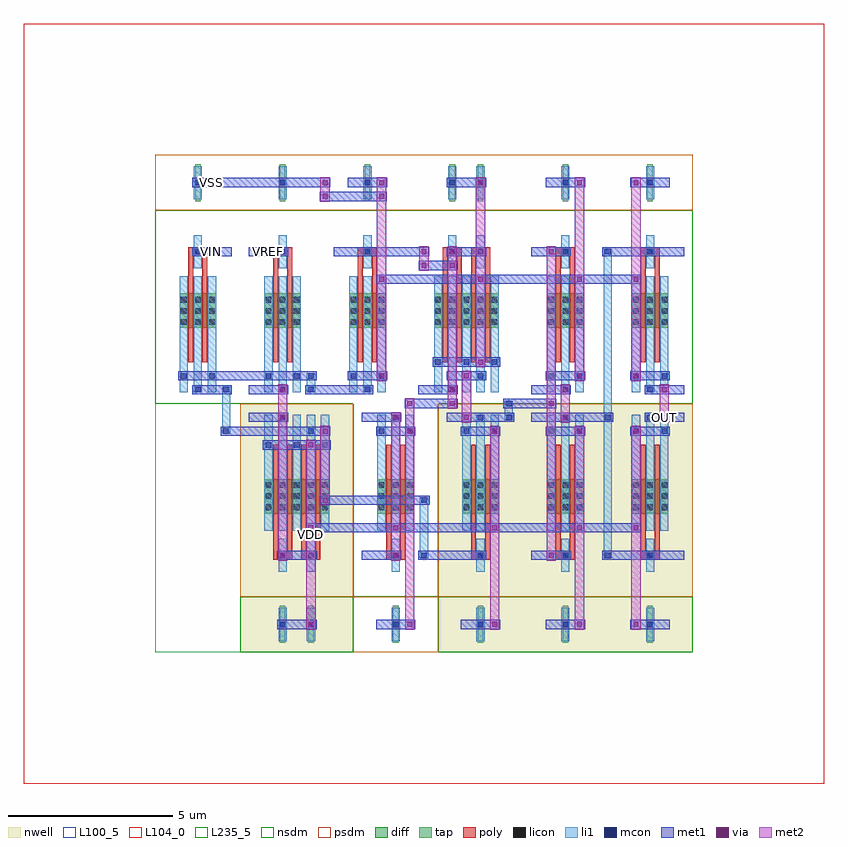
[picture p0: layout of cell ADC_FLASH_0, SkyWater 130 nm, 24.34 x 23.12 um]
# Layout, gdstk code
from math import pi, radians
import gdstk
lib = gdstk.Library(unit=1e-6, precision=1e-09)
def R(c, l, rs):  # rectangles x0, y0, x1, y1
    for r in rs: c.add(gdstk.rectangle(r[:2], r[2:], *l))
def A(c, l, x, y, w, h, nx, ny, dx, dy):  # array of equal rectangles
    R(c, l, [(x+i*dx, y+j*dy, x+i*dx+w, y+j*dy+h) for i in range(nx) for j in range(ny)])
def P(c, l, *ps):  # polygons
    for p in ps: c.add(gdstk.Polygon(p, *l))
nwell = (64, 20)
diff = (65, 20)
tap = (65, 44)
poly = (66, 20)
licon = (66, 44)
li1 = (67, 20)
mcon = (67, 44)
met1 = (68, 20)
via = (68, 44)
met2 = (69, 20)
nsdm = (93, 44)
psdm = (94, 20)
L100_5 = (100, 5)
L104_0 = (104, 0)
L235_5 = (235, 5)

nmos_s_65043269_x1_y1_16 = lib.new_cell('NMOS_S_65043269_X1_Y1_1679391342_1679391343')
R(nmos_s_65043269_x1_y1_16, diff, [(0.735,2.31,1.845,3.36)])
R(nmos_s_65043269_x1_y1_16, tap, [(1.205,6.16,1.375,7.28)])
R(nmos_s_65043269_x1_y1_16, poly, [(1,1.26,1.15,4.62), (1.43,1.26,1.58,4.62), (1,4.485,1.58,4.755)])
A(nmos_s_65043269_x1_y1_16, licon, 0.775, 2.39, 0.17, 0.17, 3, 3, 0.43, 0.34)
R(nmos_s_65043269_x1_y1_16, licon, [(1.205,4.535,1.375,4.705), (1.205,6.635,1.375,6.805)])
A(nmos_s_65043269_x1_y1_16, li1, 0.735, 0.335, 0.25, 3.53, 3, 1, 0.43, 0)
R(nmos_s_65043269_x1_y1_16, li1, [(1.165,4.115,1.415,5.125), (1.165,6.215,1.415,7.225)])
R(nmos_s_65043269_x1_y1_16, mcon, [(1.205,0.335,1.375,0.505), (0.775,0.755,0.945,0.925), (1.635,0.755,1.805,0.925), (1.205,4.535,1.375,4.705), (1.205,6.635,1.375,6.805)])
R(nmos_s_65043269_x1_y1_16, met1, [(0.26,0.28,1.46,0.56), (0.69,0.7,1.89,0.98), (0.26,4.48,1.46,4.76), (0.69,6.58,1.89,6.86)])
R(nmos_s_65043269_x1_y1_16, via, [(1.645,0.765,1.795,0.915), (1.645,6.645,1.795,6.795)])
R(nmos_s_65043269_x1_y1_16, met2, [(1.58,0.68,1.86,6.88)])
R(nmos_s_65043269_x1_y1_16, nsdm, [(0,0,2.58,5.88)])
R(nmos_s_65043269_x1_y1_16, psdm, [(0,5.88,2.58,7.56)])
R(nmos_s_65043269_x1_y1_16, L100_5, [(0,0,2.58,7.56)])

pmos_s_3683112_x1_y1_167 = lib.new_cell('PMOS_S_3683112_X1_Y1_1679391343_1679391343')
R(pmos_s_3683112_x1_y1_167, nwell, [(0,0,2.58,7.56)])
R(pmos_s_3683112_x1_y1_167, diff, [(0.735,2.31,1.845,3.36)])
R(pmos_s_3683112_x1_y1_167, tap, [(1.205,6.16,1.375,7.28)])
R(pmos_s_3683112_x1_y1_167, poly, [(1,1.26,1.15,4.62), (1.43,1.26,1.58,4.62), (1,4.485,1.58,4.755)])
A(pmos_s_3683112_x1_y1_167, licon, 0.775, 2.39, 0.17, 0.17, 3, 3, 0.43, 0.34)
R(pmos_s_3683112_x1_y1_167, licon, [(1.205,4.535,1.375,4.705), (1.205,6.635,1.375,6.805)])
A(pmos_s_3683112_x1_y1_167, li1, 0.735, 0.335, 0.25, 3.53, 3, 1, 0.43, 0)
R(pmos_s_3683112_x1_y1_167, li1, [(1.165,4.115,1.415,5.125), (1.165,6.215,1.415,7.225)])
R(pmos_s_3683112_x1_y1_167, mcon, [(1.205,0.335,1.375,0.505), (0.775,0.755,0.945,0.925), (1.635,0.755,1.805,0.925), (1.205,4.535,1.375,4.705), (1.205,6.635,1.375,6.805)])
R(pmos_s_3683112_x1_y1_167, met1, [(0.26,0.28,1.46,0.56), (0.69,0.7,1.89,0.98), (0.26,4.48,1.46,4.76), (0.69,6.58,1.89,6.86)])
R(pmos_s_3683112_x1_y1_167, via, [(1.645,0.765,1.795,0.915), (1.645,6.645,1.795,6.795)])
R(pmos_s_3683112_x1_y1_167, met2, [(1.58,0.68,1.86,6.88)])
R(pmos_s_3683112_x1_y1_167, nsdm, [(0,5.88,2.58,7.56)])
R(pmos_s_3683112_x1_y1_167, psdm, [(0,0,2.58,5.88)])
R(pmos_s_3683112_x1_y1_167, L100_5, [(0,0,2.58,7.56)])

stage2_inv_60376295_0_0_ = lib.new_cell('STAGE2_INV_60376295_0_0_1679391343')
R(stage2_inv_60376295_0_0_, li1, [(2.455,2.855,2.705,3.025), (2.455,2.855,2.705,3.025), (2.455,2.94,2.705,7.98), (2.455,7.895,2.705,8.065), (2.455,7.895,2.705,8.065), (2.455,7.895,2.705,8.065), (2.455,7.895,2.705,8.065), (2.455,7.895,2.705,8.065), (2.455,7.895,2.705,8.065), (2.455,7.98,2.705,12.18), (2.455,12.095,2.705,12.265), (2.455,12.095,2.705,12.265), (2.455,12.095,2.705,12.265), (2.455,12.095,2.705,12.265), (2.455,12.095,2.705,12.265), (2.455,12.095,2.705,12.265)])
R(stage2_inv_60376295_0_0_, mcon, [(2.495,2.855,2.665,3.025), (2.495,2.855,2.665,3.025), (2.495,7.895,2.665,8.065), (2.495,7.895,2.665,8.065), (2.495,7.895,2.665,8.065), (2.495,7.895,2.665,8.065), (2.495,7.895,2.665,8.065), (2.495,7.895,2.665,8.065), (2.495,12.095,2.665,12.265), (2.495,12.095,2.665,12.265), (2.495,12.095,2.665,12.265), (2.495,12.095,2.665,12.265), (2.495,12.095,2.665,12.265), (2.495,12.095,2.665,12.265)])
R(stage2_inv_60376295_0_0_, met1, [(1.29,2.8,2.58,3.08), (2.41,2.8,2.75,3.08), (2.41,2.8,2.75,3.08), (4.14,2.8,4.46,3.08), (4.14,2.8,4.46,3.08), (1.56,3.64,1.88,3.92), (1.56,3.64,1.88,3.92), (1.72,3.64,3.44,3.92), (3.28,3.64,3.6,3.92), (3.28,3.64,3.6,3.92), (0.7,7,1.02,7.28), (0.7,7,1.02,7.28), (3.71,7,4.03,7.28), (3.71,7,4.03,7.28), (3.71,7,4.03,7.28), (3.71,7,4.03,7.28), (0.7,7.84,1.02,8.12), (0.7,7.84,1.02,8.12), (2.41,7.84,2.75,8.12), (2.41,7.84,2.75,8.12), (2.41,7.84,2.75,8.12), (2.41,7.84,2.75,8.12), (2.41,7.84,2.75,8.12), (2.41,7.84,2.75,8.12), (2.58,7.84,3.87,8.12), (3.71,7.84,4.03,8.12), (3.71,7.84,4.03,8.12), (3.71,7.84,4.03,8.12), (3.71,7.84,4.03,8.12), (1.56,11.2,1.88,11.48), (1.56,11.2,1.88,11.48), (1.72,11.2,3.44,11.48), (3.28,11.2,3.6,11.48), (3.28,11.2,3.6,11.48), (1.29,12.04,2.58,12.32), (2.41,12.04,2.75,12.32), (2.41,12.04,2.75,12.32), (2.41,12.04,2.75,12.32), (2.41,12.04,2.75,12.32), (2.41,12.04,2.75,12.32), (2.41,12.04,2.75,12.32), (4.14,12.04,4.46,12.32), (4.14,12.04,4.46,12.32)])
P(stage2_inv_60376295_0_0_, met1, [(0,0),(0,0),(0,0),(0,0)],
  [(0,0),(0,0),(0,0),(0,0)],
  [(0,0),(0,0),(0,0),(0,0)],
  [(0,0),(0,0),(0,0),(0,0)],
  [(0,0),(0,0),(0,0),(0,0)],
  [(0,0),(0,0),(0,0),(0,0)],
  [(0,0),(0,0),(0,0),(0,0)],
  [(0,0),(0,0),(0,0),(0,0)])
R(stage2_inv_60376295_0_0_, via, [(4.225,2.865,4.375,3.015), (4.225,2.865,4.375,3.015), (1.645,3.705,1.795,3.855), (1.645,3.705,1.795,3.855), (3.365,3.705,3.515,3.855), (3.365,3.705,3.515,3.855), (0.785,7.065,0.935,7.215), (0.785,7.065,0.935,7.215), (3.795,7.065,3.945,7.215), (3.795,7.065,3.945,7.215), (3.795,7.065,3.945,7.215), (3.795,7.065,3.945,7.215), (0.785,7.905,0.935,8.055), (0.785,7.905,0.935,8.055), (3.795,7.905,3.945,8.055), (3.795,7.905,3.945,8.055), (3.795,7.905,3.945,8.055), (3.795,7.905,3.945,8.055), (1.645,11.265,1.795,11.415), (1.645,11.265,1.795,11.415), (3.365,11.265,3.515,11.415), (3.365,11.265,3.515,11.415), (4.225,12.105,4.375,12.255), (4.225,12.105,4.375,12.255)])
R(stage2_inv_60376295_0_0_, met2, [(4.16,2.78,4.44,3.1), (4.16,2.78,4.44,3.1), (4.16,2.94,4.44,12.18), (1.58,3.62,1.86,3.94), (1.58,3.62,1.86,3.94), (3.3,3.62,3.58,3.94), (3.3,3.62,3.58,3.94), (0.72,6.98,1,7.3), (0.72,6.98,1,7.3), (3.73,6.98,4.01,7.3), (3.73,6.98,4.01,7.3), (3.73,6.98,4.01,7.3), (3.73,6.98,4.01,7.3), (0.72,7.14,1,7.98), (3.73,7.14,4.01,7.98), (0.72,7.82,1,8.14), (0.72,7.82,1,8.14), (3.73,7.82,4.01,8.14), (3.73,7.82,4.01,8.14), (3.73,7.82,4.01,8.14), (3.73,7.82,4.01,8.14), (1.58,11.18,1.86,11.5), (1.58,11.18,1.86,11.5), (3.3,11.18,3.58,11.5), (3.3,11.18,3.58,11.5), (4.16,12.02,4.44,12.34), (4.16,12.02,4.44,12.34)])
P(stage2_inv_60376295_0_0_, met2, [(0,0),(0,0),(0,0),(0,0)],
  [(0,0),(0,0),(0,0),(0,0)],
  [(0,0),(0,0),(0,0),(0,0)],
  [(0,0),(0,0),(0,0),(0,0)])
R(stage2_inv_60376295_0_0_, L235_5, [(0,0,5.16,15.12)])
stage2_inv_60376295_0_0_.add(gdstk.Reference(nmos_s_65043269_x1_y1_16, (5.16,7.56), rotation=pi))
stage2_inv_60376295_0_0_.add(gdstk.Reference(nmos_s_65043269_x1_y1_16, (0,7.56), x_reflection=True))
stage2_inv_60376295_0_0_.add(gdstk.Reference(pmos_s_3683112_x1_y1_167, (5.16,7.56), rotation=pi, x_reflection=True))
stage2_inv_60376295_0_0_.add(gdstk.Reference(pmos_s_3683112_x1_y1_167, (0,7.56)))

scm_nmos_72908643_x1_y1_ = lib.new_cell('SCM_NMOS_72908643_X1_Y1_1679391343_1679391342')
R(scm_nmos_72908643_x1_y1_, diff, [(0.735,2.31,2.705,3.36)])
R(scm_nmos_72908643_x1_y1_, tap, [(1.205,6.16,1.375,7.28), (2.065,6.16,2.235,7.28)])
A(scm_nmos_72908643_x1_y1_, poly, 1, 1.26, 0.15, 3.36, 4, 1, 0.43, 0)
R(scm_nmos_72908643_x1_y1_, poly, [(1,4.485,1.58,4.755), (1.86,4.485,2.44,4.755)])
A(scm_nmos_72908643_x1_y1_, licon, 0.775, 2.39, 0.17, 0.17, 3, 3, 0.43, 0.34)
A(scm_nmos_72908643_x1_y1_, licon, 1.635, 2.39, 0.17, 0.17, 3, 3, 0.43, 0.34)
R(scm_nmos_72908643_x1_y1_, licon, [(1.205,4.535,1.375,4.705), (2.065,4.535,2.235,4.705), (1.205,6.635,1.375,6.805), (2.065,6.635,2.235,6.805)])
A(scm_nmos_72908643_x1_y1_, li1, 0.735, 0.335, 0.25, 3.53, 5, 1, 0.43, 0)
R(scm_nmos_72908643_x1_y1_, li1, [(1.165,4.115,1.415,5.125), (2.025,4.115,2.275,5.125), (1.165,6.215,1.415,7.225), (2.025,6.215,2.275,7.225)])
A(scm_nmos_72908643_x1_y1_, mcon, 0.775, 1.175, 0.17, 0.17, 3, 1, 0.86, 0)
R(scm_nmos_72908643_x1_y1_, mcon, [(1.205,0.335,1.375,0.505), (2.065,0.755,2.235,0.925), (1.205,4.535,1.375,4.705), (2.065,4.535,2.235,4.705), (1.205,6.635,1.375,6.805), (2.065,6.635,2.235,6.805)])
R(scm_nmos_72908643_x1_y1_, met1, [(0.26,0.28,1.46,0.56), (1.12,0.7,2.32,0.98), (0.69,1.12,2.75,1.4), (1.12,4.48,2.32,4.76), (1.12,6.58,2.32,6.86)])
R(scm_nmos_72908643_x1_y1_, via, [(1.215,0.345,1.365,0.495), (2.075,1.185,2.225,1.335), (1.215,4.545,1.365,4.695), (2.075,6.645,2.225,6.795)])
R(scm_nmos_72908643_x1_y1_, met2, [(1.15,0.26,1.43,4.78), (2.01,1.1,2.29,6.88)])
R(scm_nmos_72908643_x1_y1_, nsdm, [(0,0,3.44,5.88)])
R(scm_nmos_72908643_x1_y1_, psdm, [(0,5.88,3.44,7.56)])
R(scm_nmos_72908643_x1_y1_, L100_5, [(0,0,3.44,7.56)])

c_nmos_s_65043269_x1_y1_16 = lib.new_cell('NMOS_S_65043269_X1_Y1_1679391342_1679391342')
R(c_nmos_s_65043269_x1_y1_16, diff, [(0.735,2.31,1.845,3.36)])
R(c_nmos_s_65043269_x1_y1_16, tap, [(1.205,6.16,1.375,7.28)])
R(c_nmos_s_65043269_x1_y1_16, poly, [(1,1.26,1.15,4.62), (1.43,1.26,1.58,4.62), (1,4.485,1.58,4.755)])
A(c_nmos_s_65043269_x1_y1_16, licon, 0.775, 2.39, 0.17, 0.17, 3, 3, 0.43, 0.34)
R(c_nmos_s_65043269_x1_y1_16, licon, [(1.205,4.535,1.375,4.705), (1.205,6.635,1.375,6.805)])
A(c_nmos_s_65043269_x1_y1_16, li1, 0.735, 0.335, 0.25, 3.53, 3, 1, 0.43, 0)
R(c_nmos_s_65043269_x1_y1_16, li1, [(1.165,4.115,1.415,5.125), (1.165,6.215,1.415,7.225)])
R(c_nmos_s_65043269_x1_y1_16, mcon, [(1.205,0.335,1.375,0.505), (0.775,0.755,0.945,0.925), (1.635,0.755,1.805,0.925), (1.205,4.535,1.375,4.705), (1.205,6.635,1.375,6.805)])
R(c_nmos_s_65043269_x1_y1_16, met1, [(0.26,0.28,1.46,0.56), (0.69,0.7,1.89,0.98), (0.26,4.48,1.46,4.76), (0.69,6.58,1.89,6.86)])
R(c_nmos_s_65043269_x1_y1_16, via, [(1.645,0.765,1.795,0.915), (1.645,6.645,1.795,6.795)])
R(c_nmos_s_65043269_x1_y1_16, met2, [(1.58,0.68,1.86,6.88)])
R(c_nmos_s_65043269_x1_y1_16, nsdm, [(0,0,2.58,5.88)])
R(c_nmos_s_65043269_x1_y1_16, psdm, [(0,5.88,2.58,7.56)])
R(c_nmos_s_65043269_x1_y1_16, L100_5, [(0,0,2.58,7.56)])

cmb_nmos_2_83911080_0_0_ = lib.new_cell('CMB_NMOS_2_83911080_0_0_1679391342')
R(cmb_nmos_2_83911080_0_0_, met1, [(1.56,3.64,1.88,3.92), (1.56,3.64,1.88,3.92), (1.72,3.64,4.73,3.92), (4.57,3.64,4.89,3.92), (4.57,3.64,4.89,3.92), (2.85,4.06,3.17,4.34), (2.85,4.06,3.17,4.34), (3.01,4.06,3.87,4.34), (3.71,4.06,4.03,4.34), (3.71,4.06,4.03,4.34), (1.29,4.48,3.01,4.76), (2.85,4.48,3.17,4.76), (2.85,4.48,3.17,4.76)])
P(cmb_nmos_2_83911080_0_0_, met1, [(0,0),(0,0),(0,0),(0,0)],
  [(0,0),(0,0),(0,0),(0,0)],
  [(0,0),(0,0),(0,0),(0,0)])
R(cmb_nmos_2_83911080_0_0_, via, [(1.645,3.705,1.795,3.855), (1.645,3.705,1.795,3.855), (4.655,3.705,4.805,3.855), (4.655,3.705,4.805,3.855), (2.935,4.125,3.085,4.275), (2.935,4.125,3.085,4.275), (3.795,4.125,3.945,4.275), (3.795,4.125,3.945,4.275), (2.935,4.545,3.085,4.695), (2.935,4.545,3.085,4.695)])
R(cmb_nmos_2_83911080_0_0_, met2, [(1.58,3.62,1.86,3.94), (1.58,3.62,1.86,3.94), (4.59,3.62,4.87,3.94), (4.59,3.62,4.87,3.94), (2.87,4.04,3.15,4.36), (2.87,4.04,3.15,4.36), (3.73,4.04,4.01,4.36), (3.73,4.04,4.01,4.36), (2.87,4.2,3.15,4.62), (2.87,4.46,3.15,4.78), (2.87,4.46,3.15,4.78)])
P(cmb_nmos_2_83911080_0_0_, met2, [(0,0),(0,0),(0,0),(0,0)],
  [(0,0),(0,0),(0,0),(0,0)],
  [(0,0),(0,0),(0,0),(0,0)])
R(cmb_nmos_2_83911080_0_0_, L235_5, [(0,0,6.02,7.56)])
cmb_nmos_2_83911080_0_0_.add(gdstk.Reference(scm_nmos_72908643_x1_y1_, (2.58,0)))
cmb_nmos_2_83911080_0_0_.add(gdstk.Reference(c_nmos_s_65043269_x1_y1_16, (0,0)))

scm_pmos_67707602_x1_y1_ = lib.new_cell('SCM_PMOS_67707602_X1_Y1_1679391347')
R(scm_pmos_67707602_x1_y1_, nwell, [(0,0,3.44,7.56)])
R(scm_pmos_67707602_x1_y1_, diff, [(0.735,2.31,2.705,3.36)])
R(scm_pmos_67707602_x1_y1_, tap, [(1.205,6.16,1.375,7.28), (2.065,6.16,2.235,7.28)])
A(scm_pmos_67707602_x1_y1_, poly, 1, 1.26, 0.15, 3.36, 4, 1, 0.43, 0)
R(scm_pmos_67707602_x1_y1_, poly, [(1,4.485,1.58,4.755), (1.86,4.485,2.44,4.755)])
A(scm_pmos_67707602_x1_y1_, licon, 0.775, 2.39, 0.17, 0.17, 3, 3, 0.43, 0.34)
A(scm_pmos_67707602_x1_y1_, licon, 1.635, 2.39, 0.17, 0.17, 3, 3, 0.43, 0.34)
R(scm_pmos_67707602_x1_y1_, licon, [(1.205,4.535,1.375,4.705), (2.065,4.535,2.235,4.705), (1.205,6.635,1.375,6.805), (2.065,6.635,2.235,6.805)])
A(scm_pmos_67707602_x1_y1_, li1, 0.735, 0.335, 0.25, 3.53, 5, 1, 0.43, 0)
R(scm_pmos_67707602_x1_y1_, li1, [(1.165,4.115,1.415,5.125), (2.025,4.115,2.275,5.125), (1.165,6.215,1.415,7.225), (2.025,6.215,2.275,7.225)])
A(scm_pmos_67707602_x1_y1_, mcon, 0.775, 1.175, 0.17, 0.17, 3, 1, 0.86, 0)
R(scm_pmos_67707602_x1_y1_, mcon, [(1.205,0.335,1.375,0.505), (2.065,0.755,2.235,0.925), (1.205,4.535,1.375,4.705), (2.065,4.535,2.235,4.705), (1.205,6.635,1.375,6.805), (2.065,6.635,2.235,6.805)])
R(scm_pmos_67707602_x1_y1_, met1, [(0.26,0.28,1.46,0.56), (1.12,0.7,2.32,0.98), (0.69,1.12,2.75,1.4), (1.12,4.48,2.32,4.76), (1.12,6.58,2.32,6.86)])
R(scm_pmos_67707602_x1_y1_, via, [(1.215,0.345,1.365,0.495), (2.075,1.185,2.225,1.335), (1.215,4.545,1.365,4.695), (2.075,6.645,2.225,6.795)])
R(scm_pmos_67707602_x1_y1_, met2, [(1.15,0.26,1.43,4.78), (2.01,1.1,2.29,6.88)])
R(scm_pmos_67707602_x1_y1_, nsdm, [(0,5.88,3.44,7.56)])
R(scm_pmos_67707602_x1_y1_, psdm, [(0,0,3.44,5.88)])
R(scm_pmos_67707602_x1_y1_, L100_5, [(0,0,3.44,7.56)])

dcl_nmos_s_25865950_x1_y = lib.new_cell('DCL_NMOS_S_25865950_X1_Y1_1679391344')
R(dcl_nmos_s_25865950_x1_y, diff, [(0.735,2.31,1.845,3.36)])
R(dcl_nmos_s_25865950_x1_y, tap, [(1.205,6.16,1.375,7.28)])
R(dcl_nmos_s_25865950_x1_y, poly, [(1,1.26,1.15,4.62), (1.43,1.26,1.58,4.62), (1,4.485,1.58,4.755)])
A(dcl_nmos_s_25865950_x1_y, licon, 0.775, 2.39, 0.17, 0.17, 3, 3, 0.43, 0.34)
R(dcl_nmos_s_25865950_x1_y, licon, [(1.205,4.535,1.375,4.705), (1.205,6.635,1.375,6.805)])
A(dcl_nmos_s_25865950_x1_y, li1, 0.735, 0.335, 0.25, 3.53, 3, 1, 0.43, 0)
R(dcl_nmos_s_25865950_x1_y, li1, [(1.165,4.115,1.415,5.125), (1.165,6.215,1.415,7.225)])
R(dcl_nmos_s_25865950_x1_y, mcon, [(1.205,0.335,1.375,0.505), (0.775,0.755,0.945,0.925), (1.635,0.755,1.805,0.925), (1.205,4.535,1.375,4.705), (1.205,6.635,1.375,6.805)])
R(dcl_nmos_s_25865950_x1_y, met1, [(0.26,0.28,1.46,0.56), (0.69,0.7,1.89,0.98), (0.26,4.48,1.46,4.76), (0.69,6.58,1.89,6.86)])
R(dcl_nmos_s_25865950_x1_y, via, [(1.215,0.345,1.365,0.495), (1.645,0.765,1.795,0.915), (1.215,4.545,1.365,4.695), (1.645,6.645,1.795,6.795)])
R(dcl_nmos_s_25865950_x1_y, met2, [(1.15,0.26,1.43,4.78), (1.58,0.68,1.86,6.88)])
R(dcl_nmos_s_25865950_x1_y, nsdm, [(0,0,2.58,5.88)])
R(dcl_nmos_s_25865950_x1_y, psdm, [(0,5.88,2.58,7.56)])
R(dcl_nmos_s_25865950_x1_y, L100_5, [(0,0,2.58,7.56)])

c_pmos_s_3683112_x1_y1_167 = lib.new_cell('PMOS_S_3683112_X1_Y1_1679391346')
R(c_pmos_s_3683112_x1_y1_167, nwell, [(0,0,2.58,7.56)])
R(c_pmos_s_3683112_x1_y1_167, diff, [(0.735,2.31,1.845,3.36)])
R(c_pmos_s_3683112_x1_y1_167, tap, [(1.205,6.16,1.375,7.28)])
R(c_pmos_s_3683112_x1_y1_167, poly, [(1,1.26,1.15,4.62), (1.43,1.26,1.58,4.62), (1,4.485,1.58,4.755)])
A(c_pmos_s_3683112_x1_y1_167, licon, 0.775, 2.39, 0.17, 0.17, 3, 3, 0.43, 0.34)
R(c_pmos_s_3683112_x1_y1_167, licon, [(1.205,4.535,1.375,4.705), (1.205,6.635,1.375,6.805)])
A(c_pmos_s_3683112_x1_y1_167, li1, 0.735, 0.335, 0.25, 3.53, 3, 1, 0.43, 0)
R(c_pmos_s_3683112_x1_y1_167, li1, [(1.165,4.115,1.415,5.125), (1.165,6.215,1.415,7.225)])
R(c_pmos_s_3683112_x1_y1_167, mcon, [(1.205,0.335,1.375,0.505), (0.775,0.755,0.945,0.925), (1.635,0.755,1.805,0.925), (1.205,4.535,1.375,4.705), (1.205,6.635,1.375,6.805)])
R(c_pmos_s_3683112_x1_y1_167, met1, [(0.26,0.28,1.46,0.56), (0.69,0.7,1.89,0.98), (0.26,4.48,1.46,4.76), (0.69,6.58,1.89,6.86)])
R(c_pmos_s_3683112_x1_y1_167, via, [(1.645,0.765,1.795,0.915), (1.645,6.645,1.795,6.795)])
R(c_pmos_s_3683112_x1_y1_167, met2, [(1.58,0.68,1.86,6.88)])
R(c_pmos_s_3683112_x1_y1_167, nsdm, [(0,5.88,2.58,7.56)])
R(c_pmos_s_3683112_x1_y1_167, psdm, [(0,0,2.58,5.88)])
R(c_pmos_s_3683112_x1_y1_167, L100_5, [(0,0,2.58,7.56)])

nmos_4t_41712161_x1_y1_1 = lib.new_cell('NMOS_4T_41712161_X1_Y1_1679391345')
R(nmos_4t_41712161_x1_y1_1, diff, [(0.735,2.31,1.845,3.36)])
R(nmos_4t_41712161_x1_y1_1, tap, [(1.205,6.16,1.375,7.28)])
R(nmos_4t_41712161_x1_y1_1, poly, [(1,1.26,1.15,4.62), (1.43,1.26,1.58,4.62), (1,4.485,1.58,4.755)])
A(nmos_4t_41712161_x1_y1_1, licon, 0.775, 2.39, 0.17, 0.17, 3, 3, 0.43, 0.34)
R(nmos_4t_41712161_x1_y1_1, licon, [(1.205,4.535,1.375,4.705), (1.205,6.635,1.375,6.805)])
A(nmos_4t_41712161_x1_y1_1, li1, 0.735, 0.335, 0.25, 3.53, 3, 1, 0.43, 0)
R(nmos_4t_41712161_x1_y1_1, li1, [(1.165,4.115,1.415,5.125), (1.165,6.215,1.415,7.225)])
R(nmos_4t_41712161_x1_y1_1, mcon, [(1.205,0.335,1.375,0.505), (0.775,0.755,0.945,0.925), (1.635,0.755,1.805,0.925), (1.205,4.535,1.375,4.705), (1.205,6.635,1.375,6.805)])
R(nmos_4t_41712161_x1_y1_1, met1, [(0.26,0.28,1.46,0.56), (0.69,0.7,1.89,0.98), (0.26,4.48,1.46,4.76), (0.26,6.58,1.46,6.86)])
R(nmos_4t_41712161_x1_y1_1, nsdm, [(0,0,2.58,5.88)])
R(nmos_4t_41712161_x1_y1_1, psdm, [(0,5.88,2.58,7.56)])
R(nmos_4t_41712161_x1_y1_1, L100_5, [(0,0,2.58,7.56)])

adc_flash_0 = lib.new_cell('ADC_FLASH_0')
R(adc_flash_0, li1, [(8.045,2.855,8.295,3.025), (8.045,2.855,8.295,3.025), (8.045,2.94,8.295,4.62), (8.045,4.535,8.295,4.705), (8.045,4.535,8.295,4.705), (2.025,6.635,2.275,6.805), (2.025,6.635,2.275,6.805), (2.025,6.635,2.275,6.805), (2.025,6.635,2.275,6.805), (2.025,6.72,2.275,7.98), (10.625,7.055,10.875,7.225), (10.625,7.055,10.875,7.225), (10.625,7.055,10.875,7.225), (10.625,7.055,10.875,7.225), (10.625,7.14,10.875,7.56), (10.625,7.475,10.875,7.645), (10.625,7.475,10.875,7.645), (10.625,7.475,10.875,7.645), (10.625,7.475,10.875,7.645), (2.025,7.895,2.275,8.065), (2.025,7.895,2.275,8.065), (2.025,7.895,2.275,8.065), (2.025,7.895,2.275,8.065), (4.605,7.895,4.855,8.065), (4.605,7.895,4.855,8.065), (4.605,7.98,4.855,8.4), (4.605,8.315,4.855,8.485), (4.605,8.315,4.855,8.485)])
R(adc_flash_0, mcon, [(8.085,2.855,8.255,3.025), (8.085,2.855,8.255,3.025), (8.085,4.535,8.255,4.705), (8.085,4.535,8.255,4.705), (2.065,6.635,2.235,6.805), (2.065,6.635,2.235,6.805), (2.065,6.635,2.235,6.805), (2.065,6.635,2.235,6.805), (10.665,7.055,10.835,7.225), (10.665,7.055,10.835,7.225), (10.665,7.055,10.835,7.225), (10.665,7.055,10.835,7.225), (10.665,7.475,10.835,7.645), (10.665,7.475,10.835,7.645), (10.665,7.475,10.835,7.645), (10.665,7.475,10.835,7.645), (2.065,7.895,2.235,8.065), (2.065,7.895,2.235,8.065), (2.065,7.895,2.235,8.065), (2.065,7.895,2.235,8.065), (4.645,7.895,4.815,8.065), (4.645,7.895,4.815,8.065), (4.645,8.315,4.815,8.485), (4.645,8.315,4.815,8.485)])
R(adc_flash_0, met1, [(8,2.8,8.34,3.08), (8,2.8,8.34,3.08), (8.17,2.8,9.03,3.08), (4.57,3.64,4.89,3.92), (4.57,3.64,4.89,3.92), (4.57,3.64,4.89,3.92), (4.57,3.64,4.89,3.92), (4.57,3.64,4.89,3.92), (4.57,3.64,4.89,3.92), (4.73,3.64,7.31,3.92), (7.15,3.64,7.47,3.92), (7.15,3.64,7.47,3.92), (7.15,3.64,7.47,3.92), (7.15,3.64,7.47,3.92), (7.15,3.64,7.47,3.92), (7.15,3.64,7.47,3.92), (7.31,3.64,10.32,3.92), (10.16,3.64,10.48,3.92), (10.16,3.64,10.48,3.92), (10.16,3.64,10.48,3.92), (10.16,3.64,10.48,3.92), (10.32,3.64,12.9,3.92), (5,4.48,5.32,4.76), (5,4.48,5.32,4.76), (5.16,4.48,8.17,4.76), (8,4.48,8.34,4.76), (8,4.48,8.34,4.76), (1.98,6.58,2.32,6.86), (1.98,6.58,2.32,6.86), (1.98,6.58,2.32,6.86), (1.98,6.58,2.32,6.86), (2.15,6.58,3.87,6.86), (4.73,6.58,5.16,6.86), (5,6.58,5.32,6.86), (5,6.58,5.32,6.86), (9.3,7,9.62,7.28), (9.3,7,9.62,7.28), (9.89,7,10.75,7.28), (10.58,7,10.92,7.28), (10.58,7,10.92,7.28), (10.58,7,10.92,7.28), (10.58,7,10.92,7.28), (7.58,7.42,7.9,7.7), (7.58,7.42,7.9,7.7), (7.74,7.42,9.03,7.7), (8.87,7.42,9.19,7.7), (8.87,7.42,9.19,7.7), (10.58,7.42,10.92,7.7), (10.58,7.42,10.92,7.7), (10.58,7.42,10.92,7.7), (10.58,7.42,10.92,7.7), (10.75,7.42,12.04,7.7), (11.88,7.42,12.2,7.7), (11.88,7.42,12.2,7.7), (11.88,7.42,12.2,7.7), (11.88,7.42,12.2,7.7), (1.98,7.84,2.32,8.12), (1.98,7.84,2.32,8.12), (1.98,7.84,2.32,8.12), (1.98,7.84,2.32,8.12), (3.71,7.84,4.03,8.12), (3.71,7.84,4.03,8.12), (4.56,7.84,4.9,8.12), (4.56,7.84,4.9,8.12), (4.73,7.84,5.59,8.12), (1.72,8.26,3.44,8.54), (4.3,8.26,4.73,8.54), (4.56,8.26,4.9,8.54), (4.56,8.26,4.9,8.54), (9.3,8.26,9.62,8.54), (9.3,8.26,9.62,8.54), (9.89,11.2,12.9,11.48), (5,13.72,5.32,14), (5,13.72,5.32,14), (5,13.72,5.32,14), (5,13.72,5.32,14), (5.16,13.72,6.88,14), (6.72,13.72,7.04,14), (6.72,13.72,7.04,14), (6.72,13.72,7.04,14), (6.72,13.72,7.04,14), (2.15,14.14,3.01,14.42), (3.87,14.14,5.16,14.42), (5,14.14,5.32,14.42), (5,14.14,5.32,14.42), (5,14.14,5.32,14.42), (5,14.14,5.32,14.42)])
P(adc_flash_0, met1, [(0,0),(0,0),(0,0),(0,0)],
  [(0,0),(0,0),(0,0),(0,0)],
  [(0,0),(0,0),(0,0),(0,0)],
  [(0,0),(0,0),(0,0),(0,0)],
  [(0,0),(0,0),(0,0),(0,0)],
  [(0,0),(0,0),(0,0),(0,0)],
  [(0,0),(0,0),(0,0),(0,0)],
  [(0,0),(0,0),(0,0),(0,0)],
  [(0,0),(0,0),(0,0),(0,0)],
  [(0,0),(0,0),(0,0),(0,0)],
  [(0,0),(0,0),(0,0),(0,0)],
  [(0,0),(0,0),(0,0),(0,0)],
  [(0,0),(0,0),(0,0),(0,0)],
  [(0,0),(0,0),(0,0),(0,0)],
  [(0,0),(0,0),(0,0),(0,0)],
  [(0,0),(0,0),(0,0),(0,0)],
  [(0,0),(0,0),(0,0),(0,0)],
  [(0,0),(0,0),(0,0),(0,0)],
  [(0,0),(0,0),(0,0),(0,0)],
  [(0,0),(0,0),(0,0),(0,0)],
  [(0,0),(0,0),(0,0),(0,0)],
  [(0,0),(0,0),(0,0),(0,0)],
  [(0,0),(0,0),(0,0),(0,0)],
  [(0,0),(0,0),(0,0),(0,0)],
  [(0,0),(0,0),(0,0),(0,0)],
  [(0,0),(0,0),(0,0),(0,0)],
  [(0,0),(0,0),(0,0),(0,0)],
  [(0,0),(0,0),(0,0),(0,0)],
  [(0,0),(0,0),(0,0),(0,0)],
  [(0,0),(0,0),(0,0),(0,0)],
  [(0,0),(0,0),(0,0),(0,0)])
R(adc_flash_0, via, [(4.655,3.705,4.805,3.855), (4.655,3.705,4.805,3.855), (4.655,3.705,4.805,3.855), (4.655,3.705,4.805,3.855), (4.655,3.705,4.805,3.855), (4.655,3.705,4.805,3.855), (7.235,3.705,7.385,3.855), (7.235,3.705,7.385,3.855), (7.235,3.705,7.385,3.855), (7.235,3.705,7.385,3.855), (7.235,3.705,7.385,3.855), (7.235,3.705,7.385,3.855), (10.245,3.705,10.395,3.855), (10.245,3.705,10.395,3.855), (10.245,3.705,10.395,3.855), (10.245,3.705,10.395,3.855), (5.085,4.545,5.235,4.695), (5.085,4.545,5.235,4.695), (5.085,6.645,5.235,6.795), (5.085,6.645,5.235,6.795), (9.385,7.065,9.535,7.215), (9.385,7.065,9.535,7.215), (7.665,7.485,7.815,7.635), (7.665,7.485,7.815,7.635), (8.955,7.485,9.105,7.635), (8.955,7.485,9.105,7.635), (11.965,7.485,12.115,7.635), (11.965,7.485,12.115,7.635), (11.965,7.485,12.115,7.635), (11.965,7.485,12.115,7.635), (3.795,7.905,3.945,8.055), (3.795,7.905,3.945,8.055), (9.385,8.325,9.535,8.475), (9.385,8.325,9.535,8.475), (5.085,13.785,5.235,13.935), (5.085,13.785,5.235,13.935), (5.085,13.785,5.235,13.935), (5.085,13.785,5.235,13.935), (6.805,13.785,6.955,13.935), (6.805,13.785,6.955,13.935), (6.805,13.785,6.955,13.935), (6.805,13.785,6.955,13.935), (5.085,14.205,5.235,14.355), (5.085,14.205,5.235,14.355), (5.085,14.205,5.235,14.355), (5.085,14.205,5.235,14.355)])
R(adc_flash_0, met2, [(4.59,3.62,4.87,3.94), (4.59,3.62,4.87,3.94), (4.59,3.62,4.87,3.94), (4.59,3.62,4.87,3.94), (4.59,3.62,4.87,3.94), (4.59,3.62,4.87,3.94), (7.17,3.62,7.45,3.94), (7.17,3.62,7.45,3.94), (7.17,3.62,7.45,3.94), (7.17,3.62,7.45,3.94), (7.17,3.62,7.45,3.94), (7.17,3.62,7.45,3.94), (10.18,3.62,10.46,3.94), (10.18,3.62,10.46,3.94), (10.18,3.62,10.46,3.94), (10.18,3.62,10.46,3.94), (5.02,4.46,5.3,4.78), (5.02,4.46,5.3,4.78), (5.02,4.62,5.3,6.72), (5.02,6.56,5.3,6.88), (5.02,6.56,5.3,6.88), (7.6,6.72,7.88,7.56), (9.32,6.98,9.6,7.3), (9.32,6.98,9.6,7.3), (3.73,7.14,4.01,7.98), (9.32,7.14,9.6,8.4), (7.6,7.4,7.88,7.72), (7.6,7.4,7.88,7.72), (8.89,7.4,9.17,7.72), (8.89,7.4,9.17,7.72), (11.9,7.4,12.18,7.72), (11.9,7.4,12.18,7.72), (11.9,7.4,12.18,7.72), (11.9,7.4,12.18,7.72), (8.89,7.56,9.17,7.98), (3.73,7.82,4.01,8.14), (3.73,7.82,4.01,8.14), (9.32,8.24,9.6,8.56), (9.32,8.24,9.6,8.56), (5.02,13.7,5.3,14.02), (5.02,13.7,5.3,14.02), (5.02,13.7,5.3,14.02), (5.02,13.7,5.3,14.02), (6.74,13.7,7.02,14.02), (6.74,13.7,7.02,14.02), (6.74,13.7,7.02,14.02), (6.74,13.7,7.02,14.02), (5.02,13.86,5.3,14.28), (5.02,14.12,5.3,14.44), (5.02,14.12,5.3,14.44), (5.02,14.12,5.3,14.44), (5.02,14.12,5.3,14.44)])
P(adc_flash_0, met2, [(0,0),(0,0),(0,0),(0,0)],
  [(0,0),(0,0),(0,0),(0,0)],
  [(0,0),(0,0),(0,0),(0,0)],
  [(0,0),(0,0),(0,0),(0,0)],
  [(0,0),(0,0),(0,0),(0,0)],
  [(0,0),(0,0),(0,0),(0,0)],
  [(0,0),(0,0),(0,0),(0,0)],
  [(0,0),(0,0),(0,0),(0,0)],
  [(0,0),(0,0),(0,0),(0,0)],
  [(0,0),(0,0),(0,0),(0,0)],
  [(0,0),(0,0),(0,0),(0,0)],
  [(0,0),(0,0),(0,0),(0,0)],
  [(0,0),(0,0),(0,0),(0,0)],
  [(0,0),(0,0),(0,0),(0,0)],
  [(0,0),(0,0),(0,0),(0,0)],
  [(0,0),(0,0),(0,0),(0,0)],
  [(0,0),(0,0),(0,0),(0,0)],
  [(0,0),(0,0),(0,0),(0,0)],
  [(0,0),(0,0),(0,0),(0,0)],
  [(0,0),(0,0),(0,0),(0,0)],
  [(0,0),(0,0),(0,0),(0,0)],
  [(0,0),(0,0),(0,0),(0,0)],
  [(0,0),(0,0),(0,0),(0,0)])
R(adc_flash_0, L104_0, [(-4,-4,20.34,19.12)])
R(adc_flash_0, L235_5, [(0,0,16.34,15.12)])
adc_flash_0.add(gdstk.Reference(stage2_inv_60376295_0_0_, (16.34,15.12), rotation=pi))
adc_flash_0.add(gdstk.Reference(cmb_nmos_2_83911080_0_0_, (5.16,7.56)))
adc_flash_0.add(gdstk.Reference(scm_pmos_67707602_x1_y1_, (2.58,7.56), x_reflection=True))
adc_flash_0.add(gdstk.Reference(dcl_nmos_s_25865950_x1_y, (6.02,7.56), x_reflection=True))
adc_flash_0.add(gdstk.Reference(c_pmos_s_3683112_x1_y1_167, (8.6,7.56), x_reflection=True))
adc_flash_0.add(gdstk.Reference(nmos_4t_41712161_x1_y1_1, (2.58,7.56), rotation=pi, x_reflection=True))
adc_flash_0.add(gdstk.Reference(nmos_4t_41712161_x1_y1_1, (2.58,7.56)))
adc_flash_0.add(gdstk.Label('VSS', (1.72,14.28), layer=68, texttype=5))
adc_flash_0.add(gdstk.Label('VDD', (4.73,3.57), layer=69, texttype=5))
adc_flash_0.add(gdstk.Label('OUT', (15.48,7.14), layer=68, texttype=5))
adc_flash_0.add(gdstk.Label('VIN', (1.72,12.18), layer=68, texttype=5))
adc_flash_0.add(gdstk.Label('VREF', (3.44,12.18), layer=68, texttype=5))

lib.write_gds('ADC_FLASH_0.gds')
